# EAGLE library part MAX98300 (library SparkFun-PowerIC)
Mono 2.6W Class D Amplifier Datasheet: http://datasheets.maxim-ic.com/en/ds/MAX98300.pdf The MAX98300 mono 2.6W Class D amplifier provides Class AB audio performance with Class D efficiency. This device offers five selectable gain settings (0dB, 3dB, 6dB, 9dB, and 12dB) set by a single gain-select input (GAIN). Active emissions-limiting edge-rate and overshoot control circuitry greatly reduces EMI. A patented filterless spread-spectrum modulation scheme eliminates the need for output filtering found in traditional Class D devices. These features reduce application component count. The MAX98300 industry-leading 0.78mA at 3.7V (1.1mA at 5V) quiescent current extends battery life in portable applications. The MAX98300 is available in an 8-pin TDFN-EP (2mm x 2mm x 0.8mm) and a 9-bump (1.2mm x 1.2mm) WLP. Both packages are specified over the extended -40NC to +85NC temperature range.

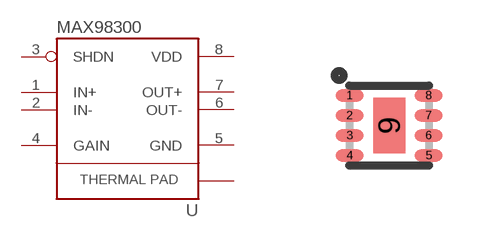
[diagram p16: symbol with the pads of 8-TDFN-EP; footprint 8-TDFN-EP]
Designator prefix U

## MAX98300ETA+  [8-TDFN-EP]
1  IN+
2  IN-
3  SHDN  in
4  GAIN  pwr
5  GND  pwr
6  OUT-
7  OUT+
8  VDD  pwr
9  GND  pwr

## Footprint 8-TDFN-EP (pad centres in mm)
TDFN - 8pin, 2mmx3mm
smd 0.7 x 0.3: 1 -0.99,0.75; 2 -0.99,0.25; 3 -0.99,-0.25; 4 -0.99,-0.75; 5 0.99,-0.75; 6 0.99,-0.25; 7 0.99,0.25; 8 0.99,0.75
smd 0.8 x 1.38: 9 0,0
